One B-rep face of a CAD part: STEP entity #159876.
In plain terms, the planar face has unit normal (0, 0, -1).
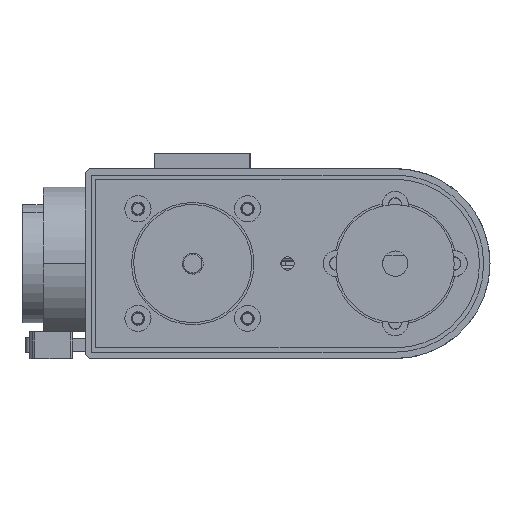
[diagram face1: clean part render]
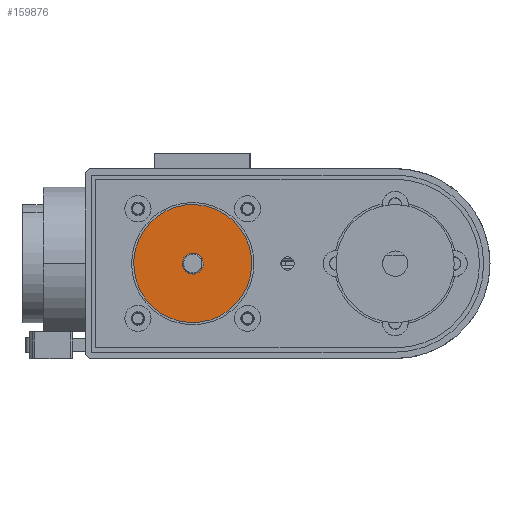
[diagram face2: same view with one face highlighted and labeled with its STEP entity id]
Its self-contained STEP definition (entity closure, numbers rounded to 3 decimals):
#159233 = VERTEX_POINT('',#159234);
#159234 = CARTESIAN_POINT('',(-2.5,0.,-2.));
#159241 = CYLINDRICAL_SURFACE('',#159242,2.5);
#159242 = AXIS2_PLACEMENT_3D('',#159243,#159244,#159245);
#159243 = CARTESIAN_POINT('',(0.,0.,13.));
#159244 = DIRECTION('',(-0.,-0.,-1.));
#159245 = DIRECTION('',(-1.,0.,0.));
#159253 = CYLINDRICAL_SURFACE('',#159254,2.5);
#159254 = AXIS2_PLACEMENT_3D('',#159255,#159256,#159257);
#159255 = CARTESIAN_POINT('',(0.,0.,13.));
#159256 = DIRECTION('',(-0.,-0.,-1.));
#159257 = DIRECTION('',(-1.,0.,0.));
#159265 = EDGE_CURVE('',#159266,#159233,#159268,.T.);
#159266 = VERTEX_POINT('',#159267);
#159267 = CARTESIAN_POINT('',(2.5,0.,-2.));
#159268 = SURFACE_CURVE('',#159269,(#159274,#159281),.PCURVE_S1.);
#159269 = CIRCLE('',#159270,2.5);
#159270 = AXIS2_PLACEMENT_3D('',#159271,#159272,#159273);
#159271 = CARTESIAN_POINT('',(0.,0.,-2.));
#159272 = DIRECTION('',(0.,0.,-1.));
#159273 = DIRECTION('',(-1.,0.,0.));
#159274 = PCURVE('',#159241,#159275);
#159275 = DEFINITIONAL_REPRESENTATION('',(#159276),#159280);
#159276 = LINE('',#159277,#159278);
#159277 = CARTESIAN_POINT('',(0.,15.));
#159278 = VECTOR('',#159279,1.);
#159279 = DIRECTION('',(1.,0.));
#159280 = ( GEOMETRIC_REPRESENTATION_CONTEXT(2) 
PARAMETRIC_REPRESENTATION_CONTEXT() REPRESENTATION_CONTEXT('2D SPACE',''
  ) );
#159281 = PCURVE('',#159282,#159287);
#159282 = PLANE('',#159283);
#159283 = AXIS2_PLACEMENT_3D('',#159284,#159285,#159286);
#159284 = CARTESIAN_POINT('',(0.,0.,-2.));
#159285 = DIRECTION('',(0.,0.,-1.));
#159286 = DIRECTION('',(-1.,0.,-0.));
#159287 = DEFINITIONAL_REPRESENTATION('',(#159288),#159292);
#159288 = CIRCLE('',#159289,2.5);
#159289 = AXIS2_PLACEMENT_2D('',#159290,#159291);
#159290 = CARTESIAN_POINT('',(0.,0.));
#159291 = DIRECTION('',(1.,0.));
#159292 = ( GEOMETRIC_REPRESENTATION_CONTEXT(2) 
PARAMETRIC_REPRESENTATION_CONTEXT() REPRESENTATION_CONTEXT('2D SPACE',''
  ) );
#159351 = EDGE_CURVE('',#159352,#159354,#159356,.T.);
#159352 = VERTEX_POINT('',#159353);
#159353 = CARTESIAN_POINT('',(-14.,0.,-2.));
#159354 = VERTEX_POINT('',#159355);
#159355 = CARTESIAN_POINT('',(14.,0.,-2.));
#159356 = SURFACE_CURVE('',#159357,(#159362,#159374),.PCURVE_S1.);
#159357 = CIRCLE('',#159358,14.);
#159358 = AXIS2_PLACEMENT_3D('',#159359,#159360,#159361);
#159359 = CARTESIAN_POINT('',(0.,0.,-2.));
#159360 = DIRECTION('',(0.,0.,-1.));
#159361 = DIRECTION('',(-1.,0.,0.));
#159362 = PCURVE('',#159363,#159368);
#159363 = CYLINDRICAL_SURFACE('',#159364,14.);
#159364 = AXIS2_PLACEMENT_3D('',#159365,#159366,#159367);
#159365 = CARTESIAN_POINT('',(0.,0.,-2.));
#159366 = DIRECTION('',(-0.,-0.,1.));
#159367 = DIRECTION('',(1.,0.,0.));
#159368 = DEFINITIONAL_REPRESENTATION('',(#159369),#159373);
#159369 = LINE('',#159370,#159371);
#159370 = CARTESIAN_POINT('',(3.142,0.));
#159371 = VECTOR('',#159372,1.);
#159372 = DIRECTION('',(-1.,0.));
#159373 = ( GEOMETRIC_REPRESENTATION_CONTEXT(2) 
PARAMETRIC_REPRESENTATION_CONTEXT() REPRESENTATION_CONTEXT('2D SPACE',''
  ) );
#159374 = PCURVE('',#159282,#159375);
#159375 = DEFINITIONAL_REPRESENTATION('',(#159376),#159380);
#159376 = CIRCLE('',#159377,14.);
#159377 = AXIS2_PLACEMENT_2D('',#159378,#159379);
#159378 = CARTESIAN_POINT('',(0.,0.));
#159379 = DIRECTION('',(1.,0.));
#159380 = ( GEOMETRIC_REPRESENTATION_CONTEXT(2) 
PARAMETRIC_REPRESENTATION_CONTEXT() REPRESENTATION_CONTEXT('2D SPACE',''
  ) );
#159398 = CYLINDRICAL_SURFACE('',#159399,14.);
#159399 = AXIS2_PLACEMENT_3D('',#159400,#159401,#159402);
#159400 = CARTESIAN_POINT('',(0.,0.,-2.));
#159401 = DIRECTION('',(-0.,-0.,1.));
#159402 = DIRECTION('',(1.,0.,0.));
#159832 = EDGE_CURVE('',#159354,#159352,#159833,.T.);
#159833 = SURFACE_CURVE('',#159834,(#159839,#159846),.PCURVE_S1.);
#159834 = CIRCLE('',#159835,14.);
#159835 = AXIS2_PLACEMENT_3D('',#159836,#159837,#159838);
#159836 = CARTESIAN_POINT('',(0.,0.,-2.));
#159837 = DIRECTION('',(0.,0.,-1.));
#159838 = DIRECTION('',(-1.,0.,0.));
#159839 = PCURVE('',#159398,#159840);
#159840 = DEFINITIONAL_REPRESENTATION('',(#159841),#159845);
#159841 = LINE('',#159842,#159843);
#159842 = CARTESIAN_POINT('',(9.425,0.));
#159843 = VECTOR('',#159844,1.);
#159844 = DIRECTION('',(-1.,0.));
#159845 = ( GEOMETRIC_REPRESENTATION_CONTEXT(2) 
PARAMETRIC_REPRESENTATION_CONTEXT() REPRESENTATION_CONTEXT('2D SPACE',''
  ) );
#159846 = PCURVE('',#159282,#159847);
#159847 = DEFINITIONAL_REPRESENTATION('',(#159848),#159852);
#159848 = CIRCLE('',#159849,14.);
#159849 = AXIS2_PLACEMENT_2D('',#159850,#159851);
#159850 = CARTESIAN_POINT('',(0.,0.));
#159851 = DIRECTION('',(1.,0.));
#159852 = ( GEOMETRIC_REPRESENTATION_CONTEXT(2) 
PARAMETRIC_REPRESENTATION_CONTEXT() REPRESENTATION_CONTEXT('2D SPACE',''
  ) );
#159876 = ADVANCED_FACE('',(#159877,#159902),#159282,.T.);
#159877 = FACE_BOUND('',#159878,.T.);
#159878 = EDGE_LOOP('',(#159879,#159901));
#159879 = ORIENTED_EDGE('',*,*,#159880,.F.);
#159880 = EDGE_CURVE('',#159233,#159266,#159881,.T.);
#159881 = SURFACE_CURVE('',#159882,(#159887,#159894),.PCURVE_S1.);
#159882 = CIRCLE('',#159883,2.5);
#159883 = AXIS2_PLACEMENT_3D('',#159884,#159885,#159886);
#159884 = CARTESIAN_POINT('',(0.,0.,-2.));
#159885 = DIRECTION('',(0.,0.,-1.));
#159886 = DIRECTION('',(-1.,0.,0.));
#159887 = PCURVE('',#159282,#159888);
#159888 = DEFINITIONAL_REPRESENTATION('',(#159889),#159893);
#159889 = CIRCLE('',#159890,2.5);
#159890 = AXIS2_PLACEMENT_2D('',#159891,#159892);
#159891 = CARTESIAN_POINT('',(0.,0.));
#159892 = DIRECTION('',(1.,0.));
#159893 = ( GEOMETRIC_REPRESENTATION_CONTEXT(2) 
PARAMETRIC_REPRESENTATION_CONTEXT() REPRESENTATION_CONTEXT('2D SPACE',''
  ) );
#159894 = PCURVE('',#159253,#159895);
#159895 = DEFINITIONAL_REPRESENTATION('',(#159896),#159900);
#159896 = LINE('',#159897,#159898);
#159897 = CARTESIAN_POINT('',(0.,15.));
#159898 = VECTOR('',#159899,1.);
#159899 = DIRECTION('',(1.,0.));
#159900 = ( GEOMETRIC_REPRESENTATION_CONTEXT(2) 
PARAMETRIC_REPRESENTATION_CONTEXT() REPRESENTATION_CONTEXT('2D SPACE',''
  ) );
#159901 = ORIENTED_EDGE('',*,*,#159265,.F.);
#159902 = FACE_BOUND('',#159903,.T.);
#159903 = EDGE_LOOP('',(#159904,#159905));
#159904 = ORIENTED_EDGE('',*,*,#159832,.T.);
#159905 = ORIENTED_EDGE('',*,*,#159351,.T.);
